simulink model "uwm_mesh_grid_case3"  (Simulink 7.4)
settings: Solver=ode45  StartTime=0.0  StopTime=8.0  RelTol=1e-4
undefined symbols (not defined in the file or in its folder): bits, D1, Delta
libraries: powerlib x77, powerlib_extras x11, dspswit3 x4, simulink x1
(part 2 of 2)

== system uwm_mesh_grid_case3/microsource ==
  E_req : Inport
  P_req : Inport  Port=2
  10 mH : powerlib/Elements/Three-Phase Series RLC Branch  DialogController=POWERSYS.PowerSysDialog  PhysicalDomain=powersysdomain  SubClassName=unknown  LeftPortType=p1  RightPortType=p1  LConnTagsString=A|B|C  RConnTagsString=A|B|C  BranchType=L  Resistance=.0028  Inductance=5e-3  Capacitance=1e-6  Measurements=None
  Current Measurement : powerlib/Measurements/Current Measurement  DialogController=POWERSYS.PowerSysDialog  SystemSampleTime=-1  PhasorSimulation=off  OutputType=Complex  PSBequivalent=0
  Gain : Gain  Gain=1/(2*pi)  ParameterDataType=fixdt(1, 16)  ParameterScaling=2^0  OutDataType=fixdt(1, 16)  OutScaling=2^0
  Mux : Mux  Inputs=3
  T1 : powerlib/Elements/Three-Phase Transformer (Two Windings)  DialogController=POWERSYS.PowerSysDialog  SystemSampleTime=-1  Winding1Connection=Delta (D1)  UNITS=SI  NominalPower=[ 45e3 , 60 ]  Winding1=[208 0.02688 0.1075/(2*pi*60)]  Winding2Connection=Yg  Winding2=[208 0.005047 .0201/(2*pi*60)]  SetSaturation=off  Rm=100.e6  Lm=7650.8  Saturation=[0 0;1359.8 0.93633;5.6659e+05 1.186]  Hysteresis=off  DataFile='hysteresis'  SetInitialFlux=off  InitialFluxes=[0.62422 -0.62422 0.54618]  Measurements=None  MoreParameters=off  BreakLoop=off  DataType=on  TransfoNumber=1
  Three-Phase V-I Measurement : powerlib/Measurements/Three-Phase V-I Measurement  DialogController=POWERSYS.PowerSysDialog  SystemSampleTime=-1  VoltageMeasurement=phase-to-ground  SetLabelV=off  LabelV=Vabc  Vpu=off  CurrentMeasurement=yes  SetLabelI=off  LabelI=Iabc  Ipu=off  Pbase=100e6  Vbase=500e3  OutputType=Complex  PhasorSimulation=off  PSBequivalent=0
  UWM_controller : Subsystem  mask{Vbase=208, Sbase=15000}
  Voltage Measurement : powerlib/Measurements/Voltage Measurement  DialogController=POWERSYS.PowerSysDialog  SystemSampleTime=-1  PhasorSimulation=off  OutputType=Complex  PSBequivalent=0
  microsource : Subsystem
  a : PMIOPort  Port=1  Side=Right
  b : PMIOPort  Port=2  Side=Right
  c : PMIOPort  Port=3  Side=Right
  m : Outport  OutDataType=fixdt(1, 16)  OutScaling=2^0
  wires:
  E_req/1 -> UWM_controller/3(E_req)
  P_req/1 -> UWM_controller/4(P_req)
  Three-Phase V-I Measurement/1 -> UWM_controller/1(v_meas)
  Three-Phase V-I Measurement/2 -> UWM_controller/2(i_meas)
  UWM_controller/1(Vpk) -> microsource/1(Vpk)
  UWM_controller/2(w) -> microsource/2(w), Gain/1
  Mux/1 -> m/1
  Voltage Measurement/1 -> Mux/1
  Current Measurement/1 -> Mux/2
  Gain/1 -> Mux/3
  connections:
  Three-Phase V-I Measurement/RConn2 -- b/RConn1 -- Voltage Measurement/LConn2
  Three-Phase V-I Measurement/RConn3 -- c/RConn1
  Current Measurement/RConn1 -- a/RConn1
  Three-Phase V-I Measurement/RConn1 -- Current Measurement/LConn1 -- Voltage Measurement/LConn1
  10 mH/LConn2 -- microsource/RConn2
  10 mH/LConn1 -- microsource/RConn1
  10 mH/LConn3 -- microsource/RConn3
  T1/LConn1 -- 10 mH/RConn1
  T1/LConn2 -- 10 mH/RConn2
  T1/LConn3 -- 10 mH/RConn3
  T1/RConn1 -- Three-Phase V-I Measurement/LConn1
  T1/RConn2 -- Three-Phase V-I Measurement/LConn2
  T1/RConn3 -- Three-Phase V-I Measurement/LConn3

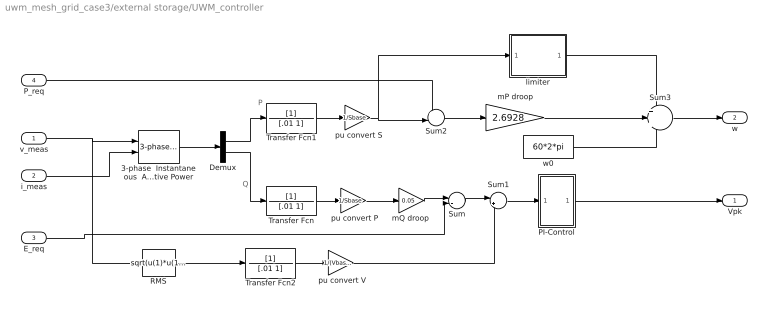
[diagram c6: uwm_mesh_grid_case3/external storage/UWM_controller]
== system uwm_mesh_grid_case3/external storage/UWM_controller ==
  note: P
  note: Q
  v_meas : Inport
  i_meas : Inport  Port=2
  E_req : Inport  Port=3
  P_req : Inport  Port=4
  " pu convert P" : Gain  Gain=1/Sbase  ParameterDataType=sfix(16)  ParameterScaling=2^0  OutDataType=sfix(16)  OutScaling=2^0
  " pu convert S" : Gain  Gain=1/Sbase  ParameterDataType=sfix(16)  ParameterScaling=2^0  OutDataType=sfix(16)  OutScaling=2^0
  " pu convert V" : Gain  Gain=1/(Vbase/sqrt(3))  ParameterDataType=sfix(16)  ParameterScaling=2^0  OutDataType=sfix(16)  OutScaling=2^0
  3-phase  Instantaneous  Active & Reactive Power : powerlib_extras/Measurements/3-phase  Instantaneous  Active & Reactive Power  DialogController=POWERSYS.PowerSysDialog  SystemSampleTime=-1
  Demux : Demux  Outputs=2
  PI-Control : Subsystem
  RMS : Fcn  Expr=sqrt(u(1)*u(1)+u(2)*u(2)+u(3)*u(3))/sqrt(3)
  Sum : Sum  Inputs=|-+  OutDataType=sfix(16)  OutScaling=2^0
  Sum1 : Sum  Inputs=|+-  OutDataType=sfix(16)  OutScaling=2^0
  Sum2 : Sum  Inputs=+-|  OutDataType=sfix(16)  OutScaling=2^0
  Sum3 : Sum  Inputs=+++  OutDataType=sfix(16)  OutScaling=2^0
  Transfer Fcn : TransferFcn  Denominator=[.01 1]
  Transfer Fcn1 : TransferFcn  Denominator=[.01 1]
  Transfer Fcn2 : TransferFcn  Denominator=[.01 1]
  limiter : Subsystem
  mP droop : Gain  Gain=2.6928  ParameterDataType=sfix(16)  ParameterScaling=2^0  OutDataType=sfix(16)  OutScaling=2^0
  "mQ droop " : Gain  Gain=0.05  ParameterDataType=sfix(16)  ParameterScaling=2^0  OutDataType=sfix(16)  OutScaling=2^0
  w0 : Constant  Value=60*2*pi  OutDataType=fixdt(1, 16)  OutScaling=2^0
  Vpk : Outport
  w : Outport  Port=2
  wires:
  Transfer Fcn2/1 -> " pu convert V"/1
  Transfer Fcn/1 -> " pu convert P"/1
  " pu convert P"/1 -> "mQ droop "/1
  Transfer Fcn1/1 -> " pu convert S"/1
  " pu convert S"/1 -> limiter/1(In1), Sum2/2
  i_meas/1 -> 3-phase  Instantaneous  Active & Reactive Power/2
  P_req/1 -> Sum2/1
  mP droop/1 -> Sum3/2
  limiter/1(Out1) -> Sum3/1
  w0/1 -> Sum3/3
  Sum2/1 -> mP droop/1
  Sum1/1 -> PI-Control/1(In1)
  Sum/1 -> Sum1/1
  "mQ droop "/1 -> Sum/1
  RMS/1 -> Transfer Fcn2/1
  Demux/2 -> Transfer Fcn/1
  Demux/1 -> Transfer Fcn1/1
  3-phase  Instantaneous  Active & Reactive Power/1 -> Demux/1
  v_meas/1 -> RMS/1, 3-phase  Instantaneous  Active & Reactive Power/1
  PI-Control/1(Out1) -> Vpk/1
  Sum3/1 -> w/1
  E_req/1 -> Sum/2
  " pu convert V"/1 -> Sum1/2

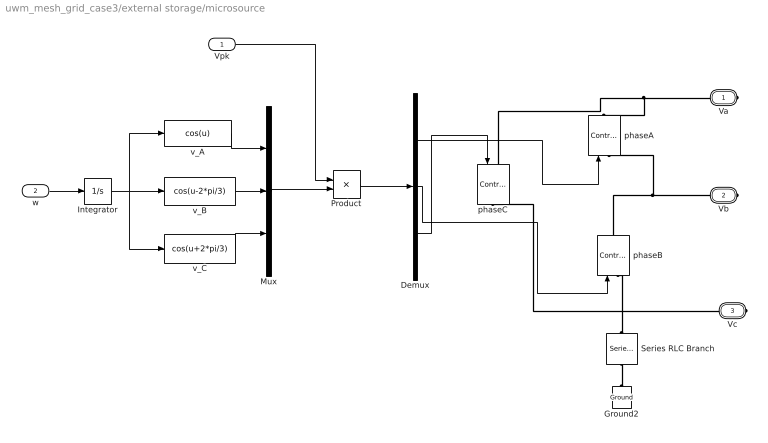
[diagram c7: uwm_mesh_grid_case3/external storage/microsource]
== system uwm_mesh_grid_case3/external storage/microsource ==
  Vpk : Inport  OutDataType=fixdt(1, 16)  OutScaling=2^0
  w : Inport  Port=2  OutDataType=fixdt(1, 16)  OutScaling=2^0
  Demux : Demux  Outputs=3
  Ground2 : powerlib/Elements/Ground  DialogController=POWERSYS.PowerSysDialog  PhysicalDomain=powersysdomain  SubClassName=unknown  LeftPortType=p1  RightPortType=p1  LConnTagsString=a
  Integrator : Integrator
  Mux : Mux  Inputs=3
  Product : Product  OutDataType=sfix(16)  OutScaling=2^0
  Series RLC Branch : powerlib/Elements/Series RLC Branch  DialogController=POWERSYS.PowerSysDialog  PhysicalDomain=powersysdomain  SubClassName=unknown  LeftPortType=p1  RightPortType=p1  LConnTagsString=__new0  RConnTagsString=__new0  BranchType=C  Resistance=1  Inductance=1e-3  SetiL0=off  InitialCurrent=0  Capacitance=1e-8  Setx0=off  InitialVoltage=0  Measurements=None
  phaseA : powerlib/Electrical Sources/Controlled Voltage Source  DialogController=POWERSYS.PowerSysDialog  SystemSampleTime=-1  Initialize=on  Source_Type=AC  Amplitude=0  Phase=0  Frequency=0  Measurements=None
  phaseB : powerlib/Electrical Sources/Controlled Voltage Source  DialogController=POWERSYS.PowerSysDialog  SystemSampleTime=-1  Initialize=on  Source_Type=AC  Amplitude=0  Phase=0  Frequency=0  Measurements=None
  phaseC : powerlib/Electrical Sources/Controlled Voltage Source  DialogController=POWERSYS.PowerSysDialog  SystemSampleTime=-1  Initialize=on  Source_Type=AC  Amplitude=0  Phase=0  Frequency=0  Measurements=None
  v_A : Fcn  Expr=cos(u)
  v_B : Fcn  Expr=cos(u-2*pi/3)
  v_C : Fcn  Expr=cos(u+2*pi/3)
  Va : PMIOPort  Tag=PMCPort  Port=1  Side=Right
  Vb : PMIOPort  Tag=PMCPort  Port=2  Side=Right
  Vc : PMIOPort  Tag=PMCPort  Port=3  Side=Right
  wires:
  Product/1 -> Demux/1
  Vpk/1 -> Product/1
  Mux/1 -> Product/2
  w/1 -> Integrator/1
  Integrator/1 -> v_A/1, v_B/1, v_C/1
  v_A/1 -> Mux/1
  v_B/1 -> Mux/2
  v_C/1 -> Mux/3
  Demux/1 -> phaseA/1
  Demux/2 -> phaseB/1
  Demux/3 -> phaseC/1
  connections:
  Vb/RConn1 -- phaseB/RConn1 -- phaseA/LConn1
  Va/RConn1 -- phaseC/LConn1 -- phaseA/RConn1
  Vc/RConn1 -- phaseC/RConn1
  Series RLC Branch/LConn1 -- phaseB/LConn1
  Series RLC Branch/RConn1 -- Ground2/LConn1

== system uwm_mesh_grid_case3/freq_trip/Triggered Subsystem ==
  In1 : Inport  OutDataType=fixdt(1, 16)  OutScaling=2^0
  Trigger : TriggerPort  TriggerType=falling
  Out1 : Outport  OutDataType=fixdt(1, 16)  OutScaling=2^0
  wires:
  In1/1 -> Out1/1

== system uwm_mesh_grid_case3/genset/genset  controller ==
  wr : Inport
  Vabc : Inport  Port=2
  Iabc : Inport  Port=3
  Preq : Inport  Port=4
  Ereq1 : Inport  Port=5
  Gain : Gain  ParameterDataType=fixdt(1, 16)  ParameterScaling=2^0  OutDataType=fixdt(1, 16)  OutScaling=2^0
  P-w droop : Subsystem
  PVQ computation : Subsystem
  Q-E droop : Subsystem
  exciter : Subsystem
  ic_engine gpvernor : Subsystem
  Pmech : Outport
  Vf : Outport  Port=2
  w : Outport  Port=3
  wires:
  P-w droop/1(w) -> w/1, ic_engine gpvernor/3(w)
  PVQ computation/1(P_pu) -> P-w droop/2(P), ic_engine gpvernor/2(Pmeas)
  PVQ computation/3(Q_pu) -> Q-E droop/2(Q)
  Q-E droop/1(Vpk) -> exciter/2(Ef_mcd_wr)
  ic_engine gpvernor/1(Pmech) -> Pmech/1
  Vabc/1 -> PVQ computation/1(Vabc)
  Iabc/1 -> PVQ computation/2(Iabc)
  exciter/1(Ef) -> Vf/1
  Preq/1 -> P-w droop/1(P_req)
  Ereq1/1 -> Q-E droop/3(E_req)
  PVQ computation/2(Vt) -> Q-E droop/1(v_meas)
  Gain/1 -> ic_engine gpvernor/1(wr), exciter/1(wr)
  wr/1 -> Gain/1

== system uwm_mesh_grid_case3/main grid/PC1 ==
  Three-Phase Series RLC Branch3 : powerlib/Elements/Three-Phase Series RLC Branch  DialogController=POWERSYS.PowerSysDialog  PhysicalDomain=powersysdomain  SubClassName=unknown  LeftPortType=p1  RightPortType=p1  LConnTagsString=A|B|C  RConnTagsString=A|B|C  BranchType=RL  Resistance=R  Inductance=L  Capacitance=1/(336*2*pi*60)  Measurements=None
  A* : PMIOPort  Tag=PMCPort  Port=1  Side=Right
  B* : PMIOPort  Tag=PMCPort  Port=2  Side=Right
  C* : PMIOPort  Tag=PMCPort  Port=3  Side=Right
  A : PMIOPort  Tag=PMCPort  Port=4  Side=Left
  B : PMIOPort  Tag=PMCPort  Port=5  Side=Left
  C : PMIOPort  Tag=PMCPort  Port=6  Side=Left
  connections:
  A*/RConn1 -- Three-Phase Series RLC Branch3/LConn1
  B*/RConn1 -- Three-Phase Series RLC Branch3/LConn2
  C*/RConn1 -- Three-Phase Series RLC Branch3/LConn3
  Three-Phase Series RLC Branch3/RConn1 -- A/RConn1
  Three-Phase Series RLC Branch3/RConn2 -- B/RConn1
  Three-Phase Series RLC Branch3/RConn3 -- C/RConn1

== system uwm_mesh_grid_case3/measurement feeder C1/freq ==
  Abs : Abs  OutDataType=fixdt(1, 16)  OutScaling=2^0
  Counter : dspswit3/Counter  Direction=Up  CountEvent=Rising edge  CounterSize=32 bits  MaxCount=255  InitialCount=0  Output=Count  HitValue=32  ResetInput=on  SamplesPerFrame=1  Ts=1  CntDtype=double  HitDtype=Logical
  Fcn : Fcn  Expr=1/u
  Gain : Gain  Gain=2*(.01/60)  ParameterDataType=fixdt(1, 16)  ParameterScaling=2^0  OutDataType=fixdt(1, 16)  OutScaling=2^0
  Ground : powerlib/Elements/Ground  DialogController=POWERSYS.PowerSysDialog  PhysicalDomain=powersysdomain  SubClassName=unknown  LeftPortType=p1  RightPortType=p1  LConnTagsString=a
  Memory : Memory
  Memory1 : Memory  InheritSampleTime=on
  Pulse Generator : DiscretePulseGenerator  PulseType=Time based  Amplitude=1  Period=.01/60  PulseWidth=50  PhaseDelay=0  SampleTime=1
  Sign : Signum
  Sign1 : Signum
  Sum : Sum  Inputs=|+-  OutDataType=fixdt(1, 16)  OutScaling=2^0
  Triggered Subsystem : Subsystem  TreatAsAtomicUnit=on
  Triggered Subsystem1 : Subsystem  TreatAsAtomicUnit=on
  Voltage  Measurement : powerlib/Measurements/Voltage Measurement  DialogController=POWERSYS.PowerSysDialog  SystemSampleTime=-1  PhasorSimulation=off  OutputType=Complex  PSBequivalent=0
  Va : PMIOPort  Tag=PMCPort  Port=1  Side=Left
  w (Hz) : Outport
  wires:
  Pulse Generator/1 -> Triggered Subsystem/Trigger, Counter/1
  Triggered Subsystem/1(Out1) -> Sign/1
  Sign/1 -> Sum/1, Memory/1
  Memory/1 -> Sum/2
  Sum/1 -> Abs/1
  Abs/1 -> Sign1/1
  Sign1/1 -> Counter/2, Triggered Subsystem1/Trigger
  Triggered Subsystem1/1(Out1) -> Gain/1
  Gain/1 -> Fcn/1
  Counter/1 -> Memory1/1
  Memory1/1 -> Triggered Subsystem1/1(In1)
  Voltage  Measurement/1 -> Triggered Subsystem/1(In1)
  Fcn/1 -> w (Hz)/1
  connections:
  Ground/LConn1 -- Voltage  Measurement/LConn2
  Va/RConn1 -- Voltage  Measurement/LConn1

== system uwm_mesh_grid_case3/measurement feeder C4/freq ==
  Abs : Abs  OutDataType=fixdt(1, 16)  OutScaling=2^0
  Counter : dspswit3/Counter  Direction=Up  CountEvent=Rising edge  CounterSize=32 bits  MaxCount=255  InitialCount=0  Output=Count  HitValue=32  ResetInput=on  SamplesPerFrame=1  Ts=1  CntDtype=double  HitDtype=Logical
  Fcn : Fcn  Expr=1/u
  Gain : Gain  Gain=2*(.01/60)  ParameterDataType=fixdt(1, 16)  ParameterScaling=2^0  OutDataType=fixdt(1, 16)  OutScaling=2^0
  Ground : powerlib/Elements/Ground  DialogController=POWERSYS.PowerSysDialog  PhysicalDomain=powersysdomain  SubClassName=unknown  LeftPortType=p1  RightPortType=p1  LConnTagsString=a
  Memory : Memory
  Memory1 : Memory  InheritSampleTime=on
  Pulse Generator : DiscretePulseGenerator  PulseType=Time based  Amplitude=1  Period=.01/60  PulseWidth=50  PhaseDelay=0  SampleTime=1
  Sign : Signum
  Sign1 : Signum
  Sum : Sum  Inputs=|+-  OutDataType=fixdt(1, 16)  OutScaling=2^0
  Triggered Subsystem : Subsystem  TreatAsAtomicUnit=on
  Triggered Subsystem1 : Subsystem  TreatAsAtomicUnit=on
  Voltage  Measurement : powerlib/Measurements/Voltage Measurement  DialogController=POWERSYS.PowerSysDialog  SystemSampleTime=-1  PhasorSimulation=off  OutputType=Complex  PSBequivalent=0
  Va : PMIOPort  Tag=PMCPort  Port=1  Side=Left
  w (Hz) : Outport
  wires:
  Pulse Generator/1 -> Triggered Subsystem/Trigger, Counter/1
  Triggered Subsystem/1(Out1) -> Sign/1
  Sign/1 -> Sum/1, Memory/1
  Memory/1 -> Sum/2
  Sum/1 -> Abs/1
  Abs/1 -> Sign1/1
  Sign1/1 -> Counter/2, Triggered Subsystem1/Trigger
  Triggered Subsystem1/1(Out1) -> Gain/1
  Gain/1 -> Fcn/1
  Counter/1 -> Memory1/1
  Memory1/1 -> Triggered Subsystem1/1(In1)
  Voltage  Measurement/1 -> Triggered Subsystem/1(In1)
  Fcn/1 -> w (Hz)/1
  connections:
  Ground/LConn1 -- Voltage  Measurement/LConn2
  Va/RConn1 -- Voltage  Measurement/LConn1

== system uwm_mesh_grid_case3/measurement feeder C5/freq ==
  Abs : Abs  OutDataType=fixdt(1, 16)  OutScaling=2^0
  Counter : dspswit3/Counter  Direction=Up  CountEvent=Rising edge  CounterSize=32 bits  MaxCount=255  InitialCount=0  Output=Count  HitValue=32  ResetInput=on  SamplesPerFrame=1  Ts=1  CntDtype=double  HitDtype=Logical
  Fcn : Fcn  Expr=1/u
  Gain : Gain  Gain=2*(.01/60)  ParameterDataType=fixdt(1, 16)  ParameterScaling=2^0  OutDataType=fixdt(1, 16)  OutScaling=2^0
  Ground : powerlib/Elements/Ground  DialogController=POWERSYS.PowerSysDialog  PhysicalDomain=powersysdomain  SubClassName=unknown  LeftPortType=p1  RightPortType=p1  LConnTagsString=a
  Memory : Memory
  Memory1 : Memory  InheritSampleTime=on
  Pulse Generator : DiscretePulseGenerator  PulseType=Time based  Amplitude=1  Period=.01/60  PulseWidth=50  PhaseDelay=0  SampleTime=1
  Sign : Signum
  Sign1 : Signum
  Sum : Sum  Inputs=|+-  OutDataType=fixdt(1, 16)  OutScaling=2^0
  Triggered Subsystem : Subsystem  TreatAsAtomicUnit=on
  Triggered Subsystem1 : Subsystem  TreatAsAtomicUnit=on
  Voltage  Measurement : powerlib/Measurements/Voltage Measurement  DialogController=POWERSYS.PowerSysDialog  SystemSampleTime=-1  PhasorSimulation=off  OutputType=Complex  PSBequivalent=0
  Va : PMIOPort  Tag=PMCPort  Port=1  Side=Left
  w (Hz) : Outport
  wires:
  Pulse Generator/1 -> Triggered Subsystem/Trigger, Counter/1
  Triggered Subsystem/1(Out1) -> Sign/1
  Sign/1 -> Sum/1, Memory/1
  Memory/1 -> Sum/2
  Sum/1 -> Abs/1
  Abs/1 -> Sign1/1
  Sign1/1 -> Counter/2, Triggered Subsystem1/Trigger
  Triggered Subsystem1/1(Out1) -> Gain/1
  Gain/1 -> Fcn/1
  Counter/1 -> Memory1/1
  Memory1/1 -> Triggered Subsystem1/1(In1)
  Voltage  Measurement/1 -> Triggered Subsystem/1(In1)
  Fcn/1 -> w (Hz)/1
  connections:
  Ground/LConn1 -- Voltage  Measurement/LConn2
  Va/RConn1 -- Voltage  Measurement/LConn1

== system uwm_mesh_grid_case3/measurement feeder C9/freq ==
  Abs : Abs  OutDataType=fixdt(1, 16)  OutScaling=2^0
  Counter : dspswit3/Counter  Direction=Up  CountEvent=Rising edge  CounterSize=32 bits  MaxCount=255  InitialCount=0  Output=Count  HitValue=32  ResetInput=on  SamplesPerFrame=1  Ts=1  CntDtype=double  HitDtype=Logical
  Fcn : Fcn  Expr=1/u
  Gain : Gain  Gain=2*(.01/60)  ParameterDataType=fixdt(1, 16)  ParameterScaling=2^0  OutDataType=fixdt(1, 16)  OutScaling=2^0
  Ground : powerlib/Elements/Ground  DialogController=POWERSYS.PowerSysDialog  PhysicalDomain=powersysdomain  SubClassName=unknown  LeftPortType=p1  RightPortType=p1  LConnTagsString=a
  Memory : Memory
  Memory1 : Memory  InheritSampleTime=on
  Pulse Generator : DiscretePulseGenerator  PulseType=Time based  Amplitude=1  Period=.01/60  PulseWidth=50  PhaseDelay=0  SampleTime=1
  Sign : Signum
  Sign1 : Signum
  Sum : Sum  Inputs=|+-  OutDataType=fixdt(1, 16)  OutScaling=2^0
  Triggered Subsystem : Subsystem  TreatAsAtomicUnit=on
  Triggered Subsystem1 : Subsystem  TreatAsAtomicUnit=on
  Voltage  Measurement : powerlib/Measurements/Voltage Measurement  DialogController=POWERSYS.PowerSysDialog  SystemSampleTime=-1  PhasorSimulation=off  OutputType=Complex  PSBequivalent=0
  Va : PMIOPort  Tag=PMCPort  Port=1  Side=Left
  w (Hz) : Outport
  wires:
  Pulse Generator/1 -> Triggered Subsystem/Trigger, Counter/1
  Triggered Subsystem/1(Out1) -> Sign/1
  Sign/1 -> Sum/1, Memory/1
  Memory/1 -> Sum/2
  Sum/1 -> Abs/1
  Abs/1 -> Sign1/1
  Sign1/1 -> Counter/2, Triggered Subsystem1/Trigger
  Triggered Subsystem1/1(Out1) -> Gain/1
  Gain/1 -> Fcn/1
  Counter/1 -> Memory1/1
  Memory1/1 -> Triggered Subsystem1/1(In1)
  Voltage  Measurement/1 -> Triggered Subsystem/1(In1)
  Fcn/1 -> w (Hz)/1
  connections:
  Ground/LConn1 -- Voltage  Measurement/LConn2
  Va/RConn1 -- Voltage  Measurement/LConn1

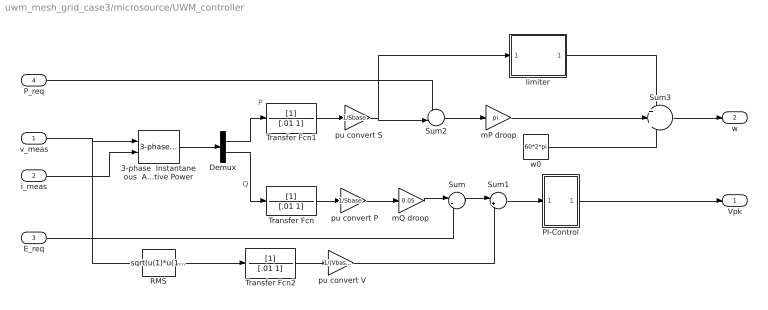
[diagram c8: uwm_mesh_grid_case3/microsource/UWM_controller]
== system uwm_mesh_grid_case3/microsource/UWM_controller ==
  note: P
  note: Q
  v_meas : Inport
  i_meas : Inport  Port=2
  E_req : Inport  Port=3
  P_req : Inport  Port=4
  " pu convert P" : Gain  Gain=1/Sbase  ParameterDataType=sfix(16)  ParameterScaling=2^0  OutDataType=sfix(16)  OutScaling=2^0
  " pu convert S" : Gain  Gain=1/Sbase  ParameterDataType=sfix(16)  ParameterScaling=2^0  OutDataType=sfix(16)  OutScaling=2^0
  " pu convert V" : Gain  Gain=1/(Vbase/sqrt(3))  ParameterDataType=sfix(16)  ParameterScaling=2^0  OutDataType=sfix(16)  OutScaling=2^0
  3-phase  Instantaneous  Active & Reactive Power : powerlib_extras/Measurements/3-phase  Instantaneous  Active & Reactive Power  DialogController=POWERSYS.PowerSysDialog  SystemSampleTime=-1
  Demux : Demux  Outputs=2
  PI-Control : Subsystem
  RMS : Fcn  Expr=sqrt(u(1)*u(1)+u(2)*u(2)+u(3)*u(3))/sqrt(3)
  Sum : Sum  Inputs=|-+  OutDataType=sfix(16)  OutScaling=2^0
  Sum1 : Sum  Inputs=|+-  OutDataType=sfix(16)  OutScaling=2^0
  Sum2 : Sum  Inputs=+-|  OutDataType=sfix(16)  OutScaling=2^0
  Sum3 : Sum  Inputs=+++  OutDataType=sfix(16)  OutScaling=2^0
  Transfer Fcn : TransferFcn  Denominator=[.01 1]
  Transfer Fcn1 : TransferFcn  Denominator=[.01 1]
  Transfer Fcn2 : TransferFcn  Denominator=[.01 1]
  limiter : Subsystem
  mP droop : Gain  Gain=pi  ParameterDataType=sfix(16)  ParameterScaling=2^0  OutDataType=sfix(16)  OutScaling=2^0
  "mQ droop " : Gain  Gain=0.05  ParameterDataType=sfix(16)  ParameterScaling=2^0  OutDataType=sfix(16)  OutScaling=2^0
  w0 : Constant  Value=60*2*pi  OutDataType=fixdt(1, 16)  OutScaling=2^0
  Vpk : Outport
  w : Outport  Port=2
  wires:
  Transfer Fcn2/1 -> " pu convert V"/1
  Transfer Fcn/1 -> " pu convert P"/1
  " pu convert P"/1 -> "mQ droop "/1
  Transfer Fcn1/1 -> " pu convert S"/1
  " pu convert S"/1 -> limiter/1(In1), Sum2/2
  i_meas/1 -> 3-phase  Instantaneous  Active & Reactive Power/2
  P_req/1 -> Sum2/1
  mP droop/1 -> Sum3/2
  limiter/1(Out1) -> Sum3/1
  w0/1 -> Sum3/3
  Sum2/1 -> mP droop/1
  Sum1/1 -> PI-Control/1(In1)
  Sum/1 -> Sum1/1
  "mQ droop "/1 -> Sum/1
  RMS/1 -> Transfer Fcn2/1
  Demux/2 -> Transfer Fcn/1
  Demux/1 -> Transfer Fcn1/1
  3-phase  Instantaneous  Active & Reactive Power/1 -> Demux/1
  v_meas/1 -> RMS/1, 3-phase  Instantaneous  Active & Reactive Power/1
  PI-Control/1(Out1) -> Vpk/1
  Sum3/1 -> w/1
  E_req/1 -> Sum/2
  " pu convert V"/1 -> Sum1/2

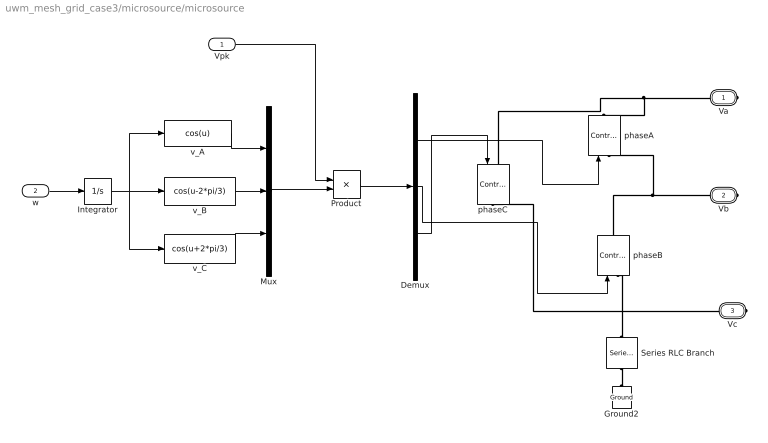
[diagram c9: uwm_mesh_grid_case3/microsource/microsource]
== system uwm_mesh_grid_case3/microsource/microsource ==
  Vpk : Inport  OutDataType=fixdt(1, 16)  OutScaling=2^0
  w : Inport  Port=2  OutDataType=fixdt(1, 16)  OutScaling=2^0
  Demux : Demux  Outputs=3
  Ground2 : powerlib/Elements/Ground  DialogController=POWERSYS.PowerSysDialog  PhysicalDomain=powersysdomain  SubClassName=unknown  LeftPortType=p1  RightPortType=p1  LConnTagsString=a
  Integrator : Integrator
  Mux : Mux  Inputs=3
  Product : Product  OutDataType=sfix(16)  OutScaling=2^0
  Series RLC Branch : powerlib/Elements/Series RLC Branch  DialogController=POWERSYS.PowerSysDialog  PhysicalDomain=powersysdomain  SubClassName=unknown  LeftPortType=p1  RightPortType=p1  LConnTagsString=__new0  RConnTagsString=__new0  BranchType=C  Resistance=1  Inductance=1e-3  SetiL0=off  InitialCurrent=0  Capacitance=1e-8  Setx0=off  InitialVoltage=0  Measurements=None
  phaseA : powerlib/Electrical Sources/Controlled Voltage Source  DialogController=POWERSYS.PowerSysDialog  SystemSampleTime=-1  Initialize=on  Source_Type=AC  Amplitude=0  Phase=0  Frequency=0  Measurements=None
  phaseB : powerlib/Electrical Sources/Controlled Voltage Source  DialogController=POWERSYS.PowerSysDialog  SystemSampleTime=-1  Initialize=on  Source_Type=AC  Amplitude=0  Phase=0  Frequency=0  Measurements=None
  phaseC : powerlib/Electrical Sources/Controlled Voltage Source  DialogController=POWERSYS.PowerSysDialog  SystemSampleTime=-1  Initialize=on  Source_Type=AC  Amplitude=0  Phase=0  Frequency=0  Measurements=None
  v_A : Fcn  Expr=cos(u)
  v_B : Fcn  Expr=cos(u-2*pi/3)
  v_C : Fcn  Expr=cos(u+2*pi/3)
  Va : PMIOPort  Tag=PMCPort  Port=1  Side=Right
  Vb : PMIOPort  Tag=PMCPort  Port=2  Side=Right
  Vc : PMIOPort  Tag=PMCPort  Port=3  Side=Right
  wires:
  Product/1 -> Demux/1
  Vpk/1 -> Product/1
  Mux/1 -> Product/2
  w/1 -> Integrator/1
  Integrator/1 -> v_A/1, v_B/1, v_C/1
  v_A/1 -> Mux/1
  v_B/1 -> Mux/2
  v_C/1 -> Mux/3
  Demux/1 -> phaseA/1
  Demux/2 -> phaseB/1
  Demux/3 -> phaseC/1
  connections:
  Vb/RConn1 -- phaseB/RConn1 -- phaseA/LConn1
  Va/RConn1 -- phaseC/LConn1 -- phaseA/RConn1
  Vc/RConn1 -- phaseC/RConn1
  Series RLC Branch/RConn1 -- Ground2/LConn1
  Series RLC Branch/LConn1 -- phaseB/LConn1

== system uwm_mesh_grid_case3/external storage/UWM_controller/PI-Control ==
  In1 : Inport
  Gain : Gain  Gain=.01  ParameterDataType=sfix(16)  ParameterScaling=2^0  OutDataType=sfix(16)  OutScaling=2^0
  Gain1 : Gain  Gain=5  ParameterDataType=sfix(16)  ParameterScaling=2^0  OutDataType=sfix(16)  OutScaling=2^0
  Gain2 : Gain  Gain=750  ParameterDataType=sfix(16)  ParameterScaling=2^0  OutDataType=sfix(16)  OutScaling=2^0
  Integrator1 : Integrator  LimitOutput=on  UpperSaturationLimit=1000  LowerSaturationLimit=-1000
  Sum4 : Sum  Inputs=|++  OutDataType=sfix(16)  OutScaling=2^0
  Out1 : Outport
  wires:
  Gain/1 -> Sum4/1
  Integrator1/1 -> Sum4/2
  In1/1 -> Gain1/1, Gain/1
  Gain1/1 -> Integrator1/1
  Sum4/1 -> Gain2/1
  Gain2/1 -> Out1/1

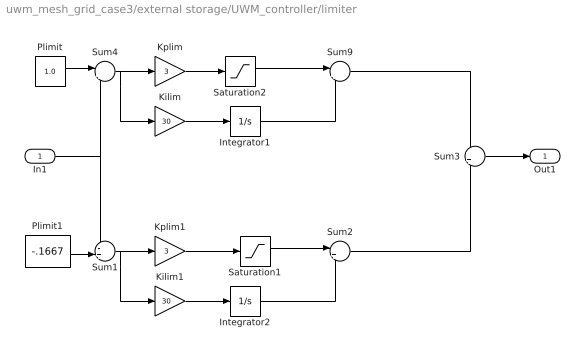
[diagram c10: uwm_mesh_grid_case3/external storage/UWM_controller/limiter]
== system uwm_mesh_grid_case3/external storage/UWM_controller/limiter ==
  In1 : Inport
  Integrator1 : Integrator  LimitOutput=on  UpperSaturationLimit=0  LowerSaturationLimit=-pi
  Integrator2 : Integrator  LimitOutput=on  UpperSaturationLimit=pi  LowerSaturationLimit=0
  Kilim : Gain  Gain=30  ParameterDataType=sfix(16)  ParameterScaling=2^0  OutDataType=sfix(16)  OutScaling=2^0
  Kilim1 : Gain  Gain=30  ParameterDataType=sfix(16)  ParameterScaling=2^0  OutDataType=sfix(16)  OutScaling=2^0
  Kplim : Gain  Gain=3  ParameterDataType=sfix(16)  ParameterScaling=2^0  OutDataType=sfix(16)  OutScaling=2^0
  Kplim1 : Gain  Gain=3  ParameterDataType=sfix(16)  ParameterScaling=2^0  OutDataType=sfix(16)  OutScaling=2^0
  Plimit : Constant  Value=1.0  OutDataType=sfix(16)  OutScaling=2^0
  Plimit1 : Constant  Value=-.1667  OutDataType=sfix(16)  OutScaling=2^0
  Saturation1 : Saturate  UpperLimit=pi  LowerLimit=0  OutDataType=fixdt(1, 16)  OutScaling=2^0
  Saturation2 : Saturate  UpperLimit=0  LowerLimit=-pi  OutDataType=fixdt(1, 16)  OutScaling=2^0
  Sum1 : Sum  Inputs=-+|  OutDataType=sfix(16)  OutScaling=2^0
  Sum2 : Sum  Inputs=|++  OutDataType=sfix(16)  OutScaling=2^0
  Sum3 : Sum  OutDataType=sfix(16)  OutScaling=2^0
  Sum4 : Sum  Inputs=|+-  OutDataType=sfix(16)  OutScaling=2^0
  Sum9 : Sum  Inputs=|++  OutDataType=sfix(16)  OutScaling=2^0
  Out1 : Outport
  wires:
  Sum3/1 -> Out1/1
  Plimit1/1 -> Sum1/2
  Integrator2/1 -> Sum2/2
  Kilim1/1 -> Integrator2/1
  Sum1/1 -> Kilim1/1, Kplim1/1
  In1/1 -> Sum1/1, Sum4/2
  Integrator1/1 -> Sum9/2
  Kilim/1 -> Integrator1/1
  Sum4/1 -> Kilim/1, Kplim/1
  Plimit/1 -> Sum4/1
  Kplim/1 -> Saturation2/1
  Saturation2/1 -> Sum9/1
  Sum9/1 -> Sum3/1
  Kplim1/1 -> Saturation1/1
  Saturation1/1 -> Sum2/1
  Sum2/1 -> Sum3/2

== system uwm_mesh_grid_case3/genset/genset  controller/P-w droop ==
  note: P
  P_req : Inport
  P : Inport  Port=2
  Sum2 : Sum  Inputs=+-|  OutDataType=sfix(16)  OutScaling=2^0
  Sum3 : Sum  Inputs=+++  OutDataType=sfix(16)  OutScaling=2^0
  limiter : Subsystem
  mP droop : Gain  Gain=pi  ParameterDataType=sfix(16)  ParameterScaling=2^0  OutDataType=sfix(16)  OutScaling=2^0
  rad2pu : Gain  Gain=1/(2*pi*60)  ParameterDataType=sfix(16)  ParameterScaling=2^0  OutDataType=sfix(16)  OutScaling=2^0
  w0 : Constant  Value=60*2*pi  OutDataType=fixdt(1, 16)  OutScaling=2^0
  w : Outport
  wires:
  P_req/1 -> Sum2/1
  mP droop/1 -> Sum3/2
  limiter/1(Out1) -> Sum3/1
  w0/1 -> Sum3/3
  Sum2/1 -> mP droop/1
  P/1 -> limiter/1(In1), Sum2/2
  Sum3/1 -> rad2pu/1
  rad2pu/1 -> w/1

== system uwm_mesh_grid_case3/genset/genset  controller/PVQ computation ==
  note: P
  note: Q
  Vabc : Inport  OutDataType=fixdt(1, 16)  OutScaling=2^0
  Iabc : Inport  Port=2  OutDataType=fixdt(1, 16)  OutScaling=2^0
  " pu convert P" : Gain  Gain=1/Sbase  ParameterDataType=sfix(16)  ParameterScaling=2^0  OutDataType=sfix(16)  OutScaling=2^0
  " pu convert S" : Gain  Gain=1/Sbase  ParameterDataType=sfix(16)  ParameterScaling=2^0  OutDataType=sfix(16)  OutScaling=2^0
  " pu convert V" : Gain  Gain=1/(Vbase/sqrt(3))  ParameterDataType=sfix(16)  ParameterScaling=2^0  OutDataType=sfix(16)  OutScaling=2^0
  3-phase  Instantaneous  Active & Reactive Power : powerlib_extras/Measurements/3-phase  Instantaneous  Active & Reactive Power  DialogController=POWERSYS.PowerSysDialog  SystemSampleTime=-1
  Demux : Demux  Outputs=2
  RMS : Fcn  Expr=sqrt(u(1)*u(1)+u(2)*u(2)+u(3)*u(3))/sqrt(3)
  Transfer Fcn1 : TransferFcn  Denominator=[.01 1]
  Transfer Fcn2 : TransferFcn  Denominator=[.01 1]
  Transfer Fcn3 : TransferFcn  Denominator=[.01 1]
  P_pu : Outport  OutDataType=fixdt(1, 16)  OutScaling=2^0
  Vt : Outport  Port=2  OutDataType=fixdt(1, 16)  OutScaling=2^0
  Q_pu : Outport  Port=3  OutDataType=fixdt(1, 16)  OutScaling=2^0
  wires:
  Iabc/1 -> 3-phase  Instantaneous  Active & Reactive Power/2
  RMS/1 -> " pu convert V"/1
  Demux/2 -> " pu convert P"/1
  Demux/1 -> " pu convert S"/1
  3-phase  Instantaneous  Active & Reactive Power/1 -> Demux/1
  Vabc/1 -> RMS/1, 3-phase  Instantaneous  Active & Reactive Power/1
  Transfer Fcn1/1 -> P_pu/1
  " pu convert S"/1 -> Transfer Fcn1/1
  Transfer Fcn2/1 -> Q_pu/1
  " pu convert P"/1 -> Transfer Fcn2/1
  Transfer Fcn3/1 -> Vt/1
  " pu convert V"/1 -> Transfer Fcn3/1

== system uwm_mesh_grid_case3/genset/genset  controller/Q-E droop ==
  note: Q
  v_meas : Inport
  Q : Inport  Port=2
  E_req : Inport  Port=3
  PI-Control : Subsystem
  Sum : Sum  Inputs=|-+  OutDataType=sfix(16)  OutScaling=2^0
  Sum1 : Sum  Inputs=|+-  OutDataType=sfix(16)  OutScaling=2^0
  "mQ droop " : Gain  Gain=0.05  ParameterDataType=sfix(16)  ParameterScaling=2^0  OutDataType=sfix(16)  OutScaling=2^0
  Vpk : Outport
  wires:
  Sum1/1 -> PI-Control/1(In1)
  Sum/1 -> Sum1/1
  "mQ droop "/1 -> Sum/1
  PI-Control/1(Out1) -> Vpk/1
  Q/1 -> "mQ droop "/1
  E_req/1 -> Sum/2
  v_meas/1 -> Sum1/2

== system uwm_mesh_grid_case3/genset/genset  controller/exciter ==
  wr : Inport  OutDataType=fixdt(1, 16)  OutScaling=2^0
  Ef_mcd_wr : Inport  Port=2  OutDataType=fixdt(1, 16)  OutScaling=2^0
  Product : Product  OutDataType=fixdt(1, 16)  OutScaling=2^0
  Saturation : Saturate  UpperLimit=10  LowerLimit=-10  OutDataType=fixdt(1, 16)  OutScaling=2^0
  Transfer Fcn : TransferFcn  Denominator=[.001 1]
  Ef : Outport  OutDataType=fixdt(1, 16)  OutScaling=2^0
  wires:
  wr/1 -> Product/2
  Ef_mcd_wr/1 -> Product/1
  Product/1 -> Saturation/1
  Saturation/1 -> Transfer Fcn/1
  Transfer Fcn/1 -> Ef/1

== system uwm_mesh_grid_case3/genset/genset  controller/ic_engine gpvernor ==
  wr : Inport  OutDataType=fixdt(1, 16)  OutScaling=2^0
  Pmeas : Inport  Port=2  OutDataType=fixdt(1, 16)  OutScaling=2^0
  w : Inport  Port=3  OutDataType=fixdt(1, 16)  OutScaling=2^0
  IC_engine : Subsystem
  governor : Subsystem
  Pmech : Outport  OutDataType=fixdt(1, 16)  OutScaling=2^0
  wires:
  governor/1(fuel_cmd) -> IC_engine/1(fuel_cmd)
  Pmeas/1 -> governor/1(Pmeas)
  IC_engine/1(Pmech) -> Pmech/1
  wr/1 -> governor/3(wr), IC_engine/2(wr)
  w/1 -> governor/2(w)

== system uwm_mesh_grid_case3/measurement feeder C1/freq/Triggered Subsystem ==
  In1 : Inport  OutDataType=fixdt(1, 16)  OutScaling=2^0
  Trigger : TriggerPort
  Out1 : Outport  OutDataType=fixdt(1, 16)  OutScaling=2^0
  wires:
  In1/1 -> Out1/1

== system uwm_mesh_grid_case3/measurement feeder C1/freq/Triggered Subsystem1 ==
  In1 : Inport  OutDataType=fixdt(1, 16)  OutScaling=2^0
  Trigger : TriggerPort
  Out1 : Outport  OutDataType=fixdt(1, 16)  OutScaling=2^0
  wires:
  In1/1 -> Out1/1

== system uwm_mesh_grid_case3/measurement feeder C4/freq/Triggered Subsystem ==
  In1 : Inport  OutDataType=fixdt(1, 16)  OutScaling=2^0
  Trigger : TriggerPort
  Out1 : Outport  OutDataType=fixdt(1, 16)  OutScaling=2^0
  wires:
  In1/1 -> Out1/1

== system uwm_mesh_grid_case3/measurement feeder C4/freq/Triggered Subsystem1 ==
  In1 : Inport  OutDataType=fixdt(1, 16)  OutScaling=2^0
  Trigger : TriggerPort
  Out1 : Outport  OutDataType=fixdt(1, 16)  OutScaling=2^0
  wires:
  In1/1 -> Out1/1

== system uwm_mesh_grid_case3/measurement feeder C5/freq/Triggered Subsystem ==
  In1 : Inport  OutDataType=fixdt(1, 16)  OutScaling=2^0
  Trigger : TriggerPort
  Out1 : Outport  OutDataType=fixdt(1, 16)  OutScaling=2^0
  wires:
  In1/1 -> Out1/1

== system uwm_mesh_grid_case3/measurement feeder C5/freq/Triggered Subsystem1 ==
  In1 : Inport  OutDataType=fixdt(1, 16)  OutScaling=2^0
  Trigger : TriggerPort
  Out1 : Outport  OutDataType=fixdt(1, 16)  OutScaling=2^0
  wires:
  In1/1 -> Out1/1

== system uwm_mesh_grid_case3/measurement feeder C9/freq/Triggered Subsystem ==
  In1 : Inport  OutDataType=fixdt(1, 16)  OutScaling=2^0
  Trigger : TriggerPort
  Out1 : Outport  OutDataType=fixdt(1, 16)  OutScaling=2^0
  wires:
  In1/1 -> Out1/1

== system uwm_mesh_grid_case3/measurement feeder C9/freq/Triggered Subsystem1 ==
  In1 : Inport  OutDataType=fixdt(1, 16)  OutScaling=2^0
  Trigger : TriggerPort
  Out1 : Outport  OutDataType=fixdt(1, 16)  OutScaling=2^0
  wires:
  In1/1 -> Out1/1

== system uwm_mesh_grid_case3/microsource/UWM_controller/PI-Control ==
  In1 : Inport
  Gain : Gain  Gain=.01  ParameterDataType=sfix(16)  ParameterScaling=2^0  OutDataType=sfix(16)  OutScaling=2^0
  Gain1 : Gain  Gain=5  ParameterDataType=sfix(16)  ParameterScaling=2^0  OutDataType=sfix(16)  OutScaling=2^0
  Gain2 : Gain  Gain=750  ParameterDataType=sfix(16)  ParameterScaling=2^0  OutDataType=sfix(16)  OutScaling=2^0
  Integrator1 : Integrator  LimitOutput=on  UpperSaturationLimit=100  LowerSaturationLimit=-100  ZeroCross=off
  Sum4 : Sum  Inputs=|++  OutDataType=sfix(16)  OutScaling=2^0
  Out1 : Outport
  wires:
  Gain/1 -> Sum4/1
  Integrator1/1 -> Sum4/2
  In1/1 -> Gain1/1, Gain/1
  Gain1/1 -> Integrator1/1
  Sum4/1 -> Gain2/1
  Gain2/1 -> Out1/1

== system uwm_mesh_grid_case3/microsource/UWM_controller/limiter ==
  In1 : Inport
  Integrator1 : Integrator  LimitOutput=on  UpperSaturationLimit=0  LowerSaturationLimit=-pi  ZeroCross=off
  Integrator2 : Integrator  LimitOutput=on  UpperSaturationLimit=pi  LowerSaturationLimit=0  ZeroCross=off
  Kilim : Gain  Gain=30  ParameterDataType=sfix(16)  ParameterScaling=2^0  OutDataType=sfix(16)  OutScaling=2^0
  Kilim1 : Gain  Gain=30  ParameterDataType=sfix(16)  ParameterScaling=2^0  OutDataType=sfix(16)  OutScaling=2^0
  Kplim : Gain  Gain=3  ParameterDataType=sfix(16)  ParameterScaling=2^0  OutDataType=sfix(16)  OutScaling=2^0
  Kplim1 : Gain  Gain=3  ParameterDataType=sfix(16)  ParameterScaling=2^0  OutDataType=sfix(16)  OutScaling=2^0
  Plimit : Constant  Value=1.0  OutDataType=sfix(16)  OutScaling=2^0
  Plimit1 : Constant  Value=0.0  OutDataType=sfix(16)  OutScaling=2^0
  Saturation1 : Saturate  UpperLimit=pi  LowerLimit=0  OutDataType=fixdt(1, 16)  OutScaling=2^0
  Saturation2 : Saturate  UpperLimit=0  LowerLimit=-pi  OutDataType=fixdt(1, 16)  OutScaling=2^0
  Sum1 : Sum  Inputs=-+|  OutDataType=sfix(16)  OutScaling=2^0
  Sum2 : Sum  Inputs=|++  OutDataType=sfix(16)  OutScaling=2^0
  Sum3 : Sum  OutDataType=sfix(16)  OutScaling=2^0
  Sum4 : Sum  Inputs=|+-  OutDataType=sfix(16)  OutScaling=2^0
  Sum9 : Sum  Inputs=|++  OutDataType=sfix(16)  OutScaling=2^0
  Out1 : Outport
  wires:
  Sum3/1 -> Out1/1
  Plimit1/1 -> Sum1/2
  Integrator2/1 -> Sum2/2
  Kilim1/1 -> Integrator2/1
  Sum1/1 -> Kilim1/1, Kplim1/1
  In1/1 -> Sum1/1, Sum4/2
  Integrator1/1 -> Sum9/2
  Kilim/1 -> Integrator1/1
  Sum4/1 -> Kilim/1, Kplim/1
  Plimit/1 -> Sum4/1
  Kplim1/1 -> Saturation1/1
  Saturation1/1 -> Sum2/1
  Kplim/1 -> Saturation2/1
  Saturation2/1 -> Sum9/1
  Sum9/1 -> Sum3/1
  Sum2/1 -> Sum3/2

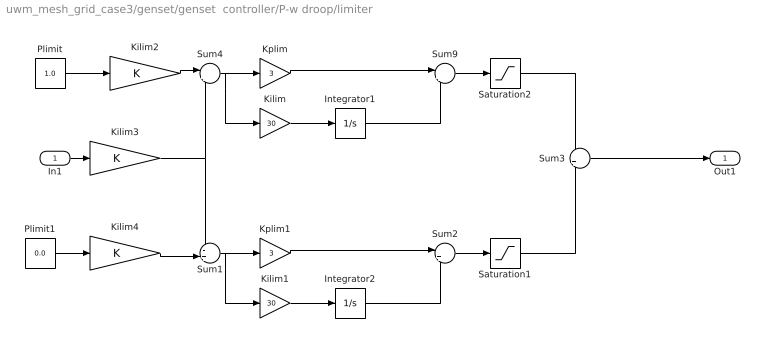
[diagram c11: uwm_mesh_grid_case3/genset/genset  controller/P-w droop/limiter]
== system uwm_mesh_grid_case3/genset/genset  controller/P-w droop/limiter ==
  In1 : Inport
  Integrator1 : Integrator  UpperSaturationLimit=0  LowerSaturationLimit=-2*pi
  Integrator2 : Integrator  UpperSaturationLimit=2*pi  LowerSaturationLimit=0
  Kilim : Gain  Gain=30  ParameterDataType=sfix(16)  ParameterScaling=2^0  OutDataType=sfix(16)  OutScaling=2^0
  Kilim1 : Gain  Gain=30  ParameterDataType=sfix(16)  ParameterScaling=2^0  OutDataType=sfix(16)  OutScaling=2^0
  Kilim2 : Gain  ParameterDataType=sfix(16)  ParameterScaling=2^0  OutDataType=sfix(16)  OutScaling=2^0
  Kilim3 : Gain  ParameterDataType=sfix(16)  ParameterScaling=2^0  OutDataType=sfix(16)  OutScaling=2^0
  Kilim4 : Gain  ParameterDataType=sfix(16)  ParameterScaling=2^0  OutDataType=sfix(16)  OutScaling=2^0
  Kplim : Gain  Gain=3  ParameterDataType=sfix(16)  ParameterScaling=2^0  OutDataType=sfix(16)  OutScaling=2^0
  Kplim1 : Gain  Gain=3  ParameterDataType=sfix(16)  ParameterScaling=2^0  OutDataType=sfix(16)  OutScaling=2^0
  Plimit : Constant  Value=1.0  OutDataType=sfix(16)  OutScaling=2^0
  Plimit1 : Constant  Value=0.0  OutDataType=sfix(16)  OutScaling=2^0
  Saturation1 : Saturate  UpperLimit=pi  LowerLimit=0  OutDataType=fixdt(1, 16)  OutScaling=2^0
  Saturation2 : Saturate  UpperLimit=0  LowerLimit=-pi  OutDataType=fixdt(1, 16)  OutScaling=2^0
  Sum1 : Sum  Inputs=-+|  OutDataType=sfix(16)  OutScaling=2^0
  Sum2 : Sum  Inputs=|++  OutDataType=sfix(16)  OutScaling=2^0
  Sum3 : Sum  OutDataType=sfix(16)  OutScaling=2^0
  Sum4 : Sum  Inputs=|+-  OutDataType=sfix(16)  OutScaling=2^0
  Sum9 : Sum  Inputs=|++  OutDataType=sfix(16)  OutScaling=2^0
  Out1 : Outport
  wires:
  Sum3/1 -> Out1/1
  Saturation2/1 -> Sum3/1
  Saturation1/1 -> Sum3/2
  Sum2/1 -> Saturation1/1
  Integrator2/1 -> Sum2/2
  Kplim1/1 -> Sum2/1
  Kilim1/1 -> Integrator2/1
  Sum1/1 -> Kilim1/1, Kplim1/1
  Sum9/1 -> Saturation2/1
  Integrator1/1 -> Sum9/2
  Kplim/1 -> Sum9/1
  Kilim/1 -> Integrator1/1
  Sum4/1 -> Kilim/1, Kplim/1
  Kilim2/1 -> Sum4/1
  Plimit/1 -> Kilim2/1
  In1/1 -> Kilim3/1
  Kilim3/1 -> Sum4/2, Sum1/1
  Plimit1/1 -> Kilim4/1
  Kilim4/1 -> Sum1/2

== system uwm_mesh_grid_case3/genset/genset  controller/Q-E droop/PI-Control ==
  In1 : Inport
  Constant1 : Constant  OutDataType=fixdt(1, 16)  OutScaling=2^0
  Gain : Gain  Gain=1000  ParameterDataType=sfix(16)  ParameterScaling=2^0  OutDataType=sfix(16)  OutScaling=2^0
  Gain1 : Gain  Gain=10  ParameterDataType=sfix(16)  ParameterScaling=2^0  OutDataType=sfix(16)  OutScaling=2^0
  Integrator1 : Integrator  InitialCondition=.88  UpperSaturationLimit=1  LowerSaturationLimit=-1
  Sum1 : Sum  Inputs=|++  OutDataType=sfix(16)  OutScaling=2^0
  Sum4 : Sum  Inputs=|++  OutDataType=sfix(16)  OutScaling=2^0
  Out1 : Outport
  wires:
  Gain/1 -> Sum4/1
  Integrator1/1 -> Sum4/2
  In1/1 -> Gain1/1, Gain/1
  Gain1/1 -> Integrator1/1
  Sum1/1 -> Out1/1
  Sum4/1 -> Sum1/1
  Constant1/1 -> Sum1/2

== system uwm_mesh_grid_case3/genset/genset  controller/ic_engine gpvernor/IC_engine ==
  fuel_cmd : Inport  OutDataType=fixdt(1, 16)  OutScaling=2^0
  wr : Inport  Port=2  OutDataType=fixdt(1, 16)  OutScaling=2^0
  Delay : TransportDelay  DelayTime=.022
  Friction_losses : Fcn  Expr=u(1)*u(1)*u(2)
  Fuel_torque : Fcn  Expr=u(1)*3.6*11.8238*0.47*1000
  Mux : Mux  Inputs=2
  Mux1 : Mux  Inputs=2
  Power Limit : Saturate  UpperLimit=1  LowerLimit=0  OutDataType=fixdt(1, 16)  OutScaling=2^0
  Sum : Sum  Inputs=|+-  OutDataType=fixdt(1, 16)  OutScaling=2^0
  Torque_to_power_pu : Fcn  Expr=u(1)*u(2)/12500
  mech_losses : Constant  Value=0.36  OutDataType=fixdt(1, 16)  OutScaling=2^0
  Pmech : Outport  OutDataType=fixdt(1, 16)  OutScaling=2^0
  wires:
  Fuel_torque/1 -> Delay/1
  fuel_cmd/1 -> Fuel_torque/1
  Delay/1 -> Mux/1
  wr/1 -> Mux/2, Mux1/1
  mech_losses/1 -> Mux1/2
  Mux1/1 -> Friction_losses/1
  Mux/1 -> Torque_to_power_pu/1
  Torque_to_power_pu/1 -> Sum/1
  Friction_losses/1 -> Sum/2
  Sum/1 -> Power Limit/1
  Power Limit/1 -> Pmech/1

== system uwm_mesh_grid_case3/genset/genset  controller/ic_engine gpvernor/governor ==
  Pmeas : Inport  OutDataType=fixdt(1, 16)  OutScaling=2^0
  w : Inport  Port=2  OutDataType=fixdt(1, 16)  OutScaling=2^0
  wr : Inport  Port=3  OutDataType=fixdt(1, 16)  OutScaling=2^0
  Gain : Gain  Gain=20  ParameterDataType=fixdt(1, 16)  ParameterScaling=2^0  OutDataType=fixdt(1, 16)  OutScaling=2^0
  Gain1 : Gain  Gain=10  ParameterDataType=fixdt(1, 16)  ParameterScaling=2^0  OutDataType=fixdt(1, 16)  OutScaling=2^0
  Integrator : Integrator  LimitOutput=on  UpperSaturationLimit=10  LowerSaturationLimit=-10
  Sum : Sum  Inputs=-+|  OutDataType=fixdt(1, 16)  OutScaling=2^0
  Sum1 : Sum  Inputs=++|  OutDataType=fixdt(1, 16)  OutScaling=2^0
  Sum2 : Sum  Inputs=++|  OutDataType=fixdt(1, 16)  OutScaling=2^0
  Te_cmd_t0_fuel : Fcn  Expr=u(1)/1.6
  Torque_limit : Saturate  UpperLimit=1000  LowerLimit=-1000  OutDataType=fixdt(1, 16)  OutScaling=2^0
  fuel_cmd : Outport  OutDataType=fixdt(1, 16)  OutScaling=2^0
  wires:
  w/1 -> Sum/2
  wr/1 -> Sum/1
  Sum/1 -> Integrator/1, Gain1/1
  Integrator/1 -> Gain/1
  Gain/1 -> Sum1/1
  Gain1/1 -> Sum1/2
  Pmeas/1 -> Sum2/1
  Sum1/1 -> Sum2/2
  Sum2/1 -> Torque_limit/1
  Torque_limit/1 -> Te_cmd_t0_fuel/1
  Te_cmd_t0_fuel/1 -> fuel_cmd/1
